VERSION 5.7 ;
  NOWIREEXTENSIONATPIN ON ;
  DIVIDERCHAR "/" ;
  BUSBITCHARS "[]" ;
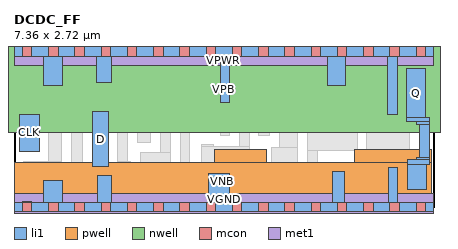
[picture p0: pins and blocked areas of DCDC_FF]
MACRO DCDC_FF
  CLASS BLOCK ;
  FOREIGN DCDC_FF ;
  ORIGIN -0.190 -0.240 ;
  SIZE 7.360 BY 2.720 ;
  PIN Q
    ANTENNADIFFAREA 0.429000 ;
    PORT
      LAYER li1 ;
        RECT 7.075 1.815 7.405 2.660 ;
        RECT 7.075 1.735 7.465 1.815 ;
        RECT 7.250 1.685 7.465 1.735 ;
        RECT 7.295 1.105 7.465 1.685 ;
        RECT 7.240 1.065 7.465 1.105 ;
        RECT 7.085 0.980 7.465 1.065 ;
        RECT 7.085 0.545 7.415 0.980 ;
    END
  END Q
  PIN CLK
    ANTENNAGATEAREA 0.159000 ;
    PORT
      LAYER li1 ;
        RECT 0.280 1.215 0.630 1.865 ;
    END
  END CLK
  PIN D
    ANTENNAGATEAREA 0.126000 ;
    PORT
      LAYER li1 ;
        RECT 1.560 0.955 1.840 1.905 ;
    END
  END D
  PIN VNB
    PORT
      LAYER pwell ;
        RECT 3.710 1.025 4.620 1.245 ;
        RECT 6.155 1.025 7.505 1.255 ;
        RECT 0.195 0.345 7.505 1.025 ;
        RECT 0.335 0.155 0.505 0.345 ;
    END
  END VNB
  PIN VPB
    PORT
      LAYER nwell ;
        RECT 0.000 1.545 7.740 3.150 ;
    END
  END VPB
  PIN VPWR
    USE POWER ;
    PORT
      LAYER li1 ;
        RECT 0.190 2.875 7.550 3.045 ;
        RECT 0.705 2.375 1.035 2.875 ;
        RECT 1.630 2.415 1.895 2.875 ;
        RECT 3.800 2.075 3.970 2.875 ;
        RECT 5.680 2.375 5.995 2.875 ;
        RECT 6.735 1.865 6.905 2.875 ;
      LAYER mcon ;
        RECT 0.335 2.875 0.505 3.045 ;
        RECT 0.795 2.875 0.965 3.045 ;
        RECT 1.255 2.875 1.425 3.045 ;
        RECT 1.715 2.875 1.885 3.045 ;
        RECT 2.175 2.875 2.345 3.045 ;
        RECT 2.635 2.875 2.805 3.045 ;
        RECT 3.095 2.875 3.265 3.045 ;
        RECT 3.555 2.875 3.725 3.045 ;
        RECT 4.015 2.875 4.185 3.045 ;
        RECT 4.475 2.875 4.645 3.045 ;
        RECT 4.935 2.875 5.105 3.045 ;
        RECT 5.395 2.875 5.565 3.045 ;
        RECT 5.855 2.875 6.025 3.045 ;
        RECT 6.315 2.875 6.485 3.045 ;
        RECT 6.775 2.875 6.945 3.045 ;
        RECT 7.235 2.875 7.405 3.045 ;
      LAYER met1 ;
        RECT 0.190 2.720 7.550 3.200 ;
    END
  END VPWR
  PIN VGND
    USE GROUND ;
    PORT
      LAYER li1 ;
        RECT 0.705 0.325 1.035 0.705 ;
        RECT 1.645 0.325 1.895 0.785 ;
        RECT 3.590 0.325 3.960 0.825 ;
        RECT 5.775 0.325 5.985 0.855 ;
        RECT 6.745 0.325 6.915 0.935 ;
        RECT 0.190 0.155 7.550 0.325 ;
      LAYER mcon ;
        RECT 0.335 0.155 0.505 0.325 ;
        RECT 0.795 0.155 0.965 0.325 ;
        RECT 1.255 0.155 1.425 0.325 ;
        RECT 1.715 0.155 1.885 0.325 ;
        RECT 2.175 0.155 2.345 0.325 ;
        RECT 2.635 0.155 2.805 0.325 ;
        RECT 3.095 0.155 3.265 0.325 ;
        RECT 3.555 0.155 3.725 0.325 ;
        RECT 4.015 0.155 4.185 0.325 ;
        RECT 4.475 0.155 4.645 0.325 ;
        RECT 4.935 0.155 5.105 0.325 ;
        RECT 5.395 0.155 5.565 0.325 ;
        RECT 5.855 0.155 6.025 0.325 ;
        RECT 6.315 0.155 6.485 0.325 ;
        RECT 6.775 0.155 6.945 0.325 ;
        RECT 7.235 0.155 7.405 0.325 ;
      LAYER met1 ;
        RECT 0.190 0.000 7.550 0.480 ;
    END
  END VGND
  OBS
      LAYER li1 ;
        RECT 0.365 2.205 0.535 2.705 ;
        RECT 0.365 2.035 1.030 2.205 ;
        RECT 0.800 1.045 1.030 2.035 ;
        RECT 0.365 0.875 1.030 1.045 ;
        RECT 0.365 0.585 0.535 0.875 ;
        RECT 1.205 0.585 1.390 2.705 ;
        RECT 2.065 2.280 2.315 2.705 ;
        RECT 2.525 2.430 3.630 2.600 ;
        RECT 2.010 2.150 2.315 2.280 ;
        RECT 2.010 1.045 2.180 2.150 ;
        RECT 2.350 1.365 2.590 1.960 ;
        RECT 2.760 1.895 3.290 2.260 ;
        RECT 2.760 1.195 2.930 1.895 ;
        RECT 3.460 1.815 3.630 2.430 ;
        RECT 4.140 2.375 4.390 2.705 ;
        RECT 4.615 2.405 5.500 2.575 ;
        RECT 3.460 1.725 3.970 1.815 ;
        RECT 2.010 0.915 2.235 1.045 ;
        RECT 2.405 0.975 2.930 1.195 ;
        RECT 3.100 1.555 3.970 1.725 ;
        RECT 2.065 0.775 2.235 0.915 ;
        RECT 3.100 0.775 3.270 1.555 ;
        RECT 3.800 1.485 3.970 1.555 ;
        RECT 3.480 1.305 3.680 1.335 ;
        RECT 4.140 1.305 4.310 2.375 ;
        RECT 4.480 1.485 4.670 2.205 ;
        RECT 3.480 1.005 4.310 1.305 ;
        RECT 4.840 1.275 5.160 2.235 ;
        RECT 2.065 0.605 2.400 0.775 ;
        RECT 2.595 0.605 3.270 0.775 ;
        RECT 4.140 0.775 4.310 1.005 ;
        RECT 4.695 0.945 5.160 1.275 ;
        RECT 5.330 1.565 5.500 2.405 ;
        RECT 6.225 2.145 6.565 2.705 ;
        RECT 5.670 1.770 6.565 2.145 ;
        RECT 6.375 1.565 6.565 1.770 ;
        RECT 5.330 1.235 6.205 1.565 ;
        RECT 6.375 1.235 7.125 1.565 ;
        RECT 5.330 0.775 5.500 1.235 ;
        RECT 6.375 1.065 6.575 1.235 ;
        RECT 4.140 0.605 4.545 0.775 ;
        RECT 4.715 0.605 5.500 0.775 ;
        RECT 6.245 0.540 6.575 1.065 ;
      LAYER mcon ;
        RECT 0.820 2.025 0.990 2.195 ;
        RECT 1.215 1.685 1.385 1.855 ;
        RECT 2.920 2.025 3.090 2.195 ;
        RECT 2.405 1.685 2.575 1.855 ;
        RECT 4.490 2.025 4.660 2.195 ;
        RECT 4.925 1.685 5.095 1.855 ;
      LAYER met1 ;
        RECT 0.760 2.180 1.050 2.225 ;
        RECT 2.860 2.180 3.150 2.225 ;
        RECT 4.430 2.180 4.720 2.225 ;
        RECT 0.760 2.040 4.720 2.180 ;
        RECT 0.760 1.995 1.050 2.040 ;
        RECT 2.860 1.995 3.150 2.040 ;
        RECT 4.430 1.995 4.720 2.040 ;
        RECT 1.155 1.840 1.445 1.885 ;
        RECT 2.345 1.840 2.635 1.885 ;
        RECT 4.865 1.840 5.155 1.885 ;
        RECT 1.155 1.700 5.155 1.840 ;
        RECT 1.155 1.655 1.445 1.700 ;
        RECT 2.345 1.655 2.635 1.700 ;
        RECT 4.865 1.655 5.155 1.700 ;
  END
END DCDC_FF
END LIBRARY
